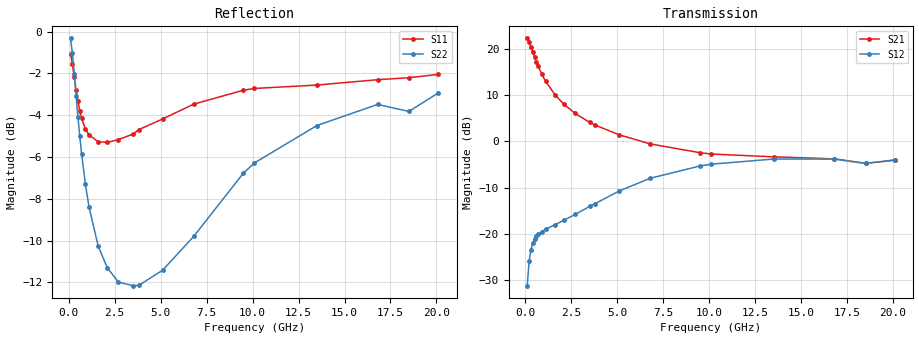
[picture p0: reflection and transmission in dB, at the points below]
!  Infineon Technologies AG
! BFR380L3 , PF131585-7, No.6, Th 09.10.01, soldered on pcb-board, measured with PP GSG850
!  Vce=4.0 V,  Ic=4.0 mA
! Common Emitter S-Parameters:  15. November 2001
#  GHz  S  MA  R  50
! f  S11  S21  S12  S22
! GHz  Mag  Ang  Mag  Ang  Mag  Ang  Mag  Ang
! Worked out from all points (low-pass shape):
!   201 points, 100 MHz to 20.1 GHz, reference 50 ohm
!   highest |S21| = 22.32 dB at 100 MHz (marker M1); lowest = -4.7 dB at 18.5 GHz (marker M2)
!   |S21| within 3 dB of the highest: start of sweep to 405.5 MHz
!   lowest |S11| = -5.3 dB at 2.1 GHz (marker M3), VSWR 3.38, Z = 14.8 + j0.147 ohm
!   |S11| at or under -10 dB: nowhere
!   |S22| runs from -12.2 to -0.3 dB; largest |S21 - S12| = 13
!   S11 on the Smith chart (normalised r, x): 100 MHz: 1.32, -4.35; 400 MHz: 0.36, -1.10; 1.1 GHz: 0.30, -0.30; 3.8 GHz: 0.29, +0.29; 9.5 GHz: 0.36, +1.09; 20.1 GHz: 0.97, +2.55
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0.1  0.8851 -23.9  13.06 163.7  0.02753 76.9  0.964 -13.7
0.2  0.836 -45.9  11.88 149.3  0.05032 66.2  0.8873 -25.8
0.3  0.7798 -65.4  10.57 137.3  0.06742 57.5  0.7926 -35.3
0.4  0.7252 -81.3  9.308 127.6  0.07935 51.3  0.7028 -42.6
0.5  0.6822 -94.8  8.199 119.7  0.0876 46.8  0.6257 -48.0
0.6  0.6446 -106.2  7.26 113.4  0.09401 43.9  0.5621 -52.2
0.7  0.6205 -115.9  6.495 107.9  0.09884 41.7  0.5101 -55.4
0.9  0.5857 -131.5  5.316 99.2  0.1062 39.6  0.433 -60.1
1.1  0.5668 -143.6  4.488 92.3  0.1123 38.9  0.3814 -63.6
1.6  0.5454 -165.2  3.219 79.0  0.1255 40.6  0.3069 -70.1
2.1  0.5433 179.6  2.52 68.6  0.1407 43.4  0.2722 -76.6
2.7  0.5519 165.4  2.017 57.9  0.1624 46.7  0.2516 -85.8
3.5  0.5688 150.0  1.607 45.7  0.1987 49.3  0.2467 -98.9
3.8  0.5826 145.4  1.503 41.7  0.2128 49.7  0.247 -105.6
5.1  0.6182 126.2  1.182 26.0  0.2915 47.7  0.2685 -131.1
6.8  0.6709 105.7  0.9406 10.7  0.4008 39.5  0.3238 -166.0
9.5  0.7245 81.9  0.7565 -4.5  0.5439 20.4  0.4587 150.9
10.1  0.7314 77.7  0.7319 -6.8  0.5681 16.1  0.4853 142.5
13.5  0.7453 59.2  0.6822 -20.1  0.6458 -7.5  0.5963 105.5
16.8  0.7676 47.4  0.649 -31.6  0.6452 -24.7  0.6699 80.5
18.5  0.776 45.6  0.5803 -39.5  0.5791 -33.4  0.6444 74.0
20.1  0.7905 38.3  0.6269 -42.8  0.6322 -38.7  0.7136 62.8
